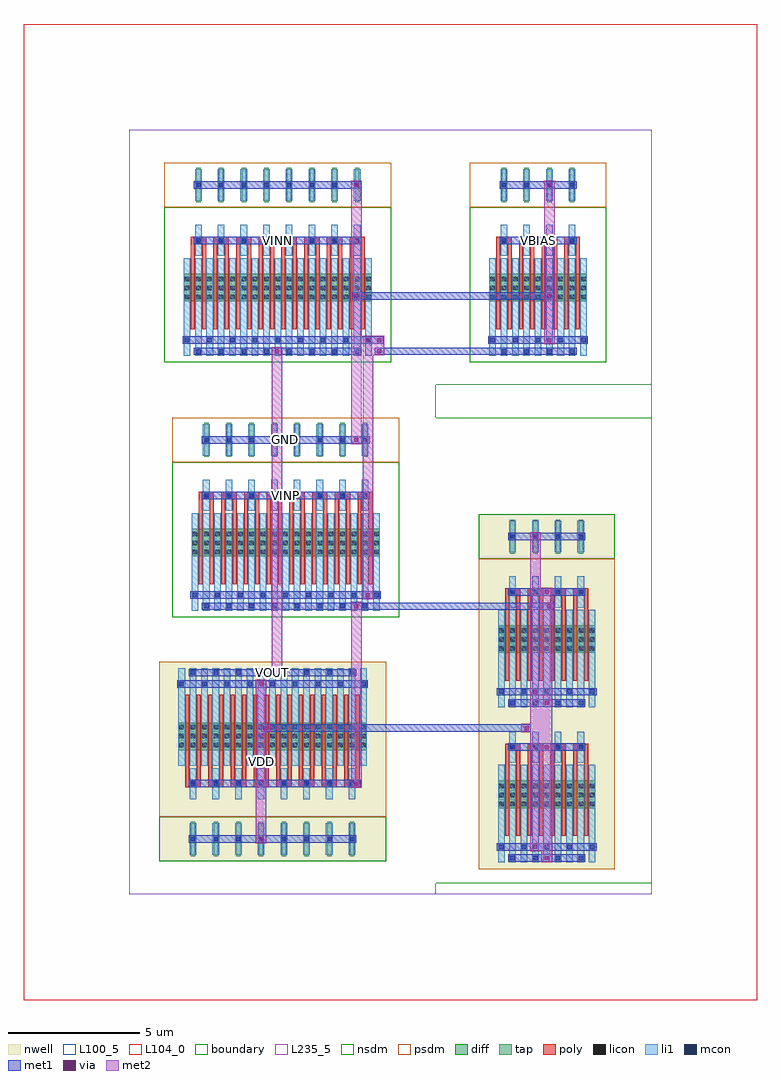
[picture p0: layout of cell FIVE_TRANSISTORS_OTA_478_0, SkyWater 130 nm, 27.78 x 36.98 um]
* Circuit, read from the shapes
.subckt FIVE_TRANSISTORS_OTA_478_0 GND VBIAS VDD VINN VINP VOUT
XM1 VOUT VINN n1 GND sky130_fd_pr__nfet_01v8 w=1.05 l=0.15 m=16
XM2 n2 VINP n1 GND sky130_fd_pr__nfet_01v8 w=1.05 l=0.15 m=16
XM3 n1 VBIAS GND GND sky130_fd_pr__nfet_01v8 w=1.05 l=0.15 m=8
XM4 VOUT n2 VDD VDD sky130_fd_pr__pfet_01v8 w=1.05 l=0.15 m=16
XM5 n2 n2 VDD VDD sky130_fd_pr__pfet_01v8 w=1.05 l=0.15 m=16
.ends

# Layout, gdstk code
from math import pi, radians
import gdstk
lib = gdstk.Library(unit=1e-6, precision=1e-09)
def R(c, l, rs):  # rectangles x0, y0, x1, y1
    for r in rs: c.add(gdstk.rectangle(r[:2], r[2:], *l))
def A(c, l, x, y, w, h, nx, ny, dx, dy):  # array of equal rectangles
    R(c, l, [(x+i*dx, y+j*dy, x+i*dx+w, y+j*dy+h) for i in range(nx) for j in range(ny)])
def P(c, l, *ps):  # polygons
    for p in ps: c.add(gdstk.Polygon(p, *l))
nwell = (64, 20)
diff = (65, 20)
tap = (65, 44)
poly = (66, 20)
licon = (66, 44)
li1 = (67, 20)
mcon = (67, 44)
met1 = (68, 20)
via = (68, 44)
met2 = (69, 20)
nsdm = (93, 44)
psdm = (94, 20)
L100_5 = (100, 5)
L104_0 = (104, 0)
boundary = (235, 4)
L235_5 = (235, 5)

dcl_pmos_s_58408510_x4_y = lib.new_cell('DCL_PMOS_S_58408510_X4_Y2_1746738309')
R(dcl_pmos_s_58408510_x4_y, nwell, [(1.39,0.54,6.55,13.98)])
R(dcl_pmos_s_58408510_x4_y, diff, [(2.125,2.85,5.815,3.9), (2.125,8.73,5.815,9.78)])
A(dcl_pmos_s_58408510_x4_y, tap, 2.595, 12.495, 0.17, 1.29, 4, 1, 0.86, 0)
A(dcl_pmos_s_58408510_x4_y, poly, 2.39, 1.8, 0.15, 3.36, 8, 2, 0.43, 5.88)
A(dcl_pmos_s_58408510_x4_y, poly, 2.39, 5.025, 0.58, 0.27, 4, 2, 0.86, 5.88)
A(dcl_pmos_s_58408510_x4_y, licon, 2.165, 2.93, 0.17, 0.17, 3, 3, 0.43, 0.34)
A(dcl_pmos_s_58408510_x4_y, licon, 3.025, 2.93, 0.17, 0.17, 3, 3, 0.43, 0.34)
A(dcl_pmos_s_58408510_x4_y, licon, 3.885, 2.93, 0.17, 0.17, 3, 3, 0.43, 0.34)
A(dcl_pmos_s_58408510_x4_y, licon, 4.745, 2.93, 0.17, 0.17, 3, 3, 0.43, 0.34)
A(dcl_pmos_s_58408510_x4_y, licon, 2.595, 5.075, 0.17, 0.17, 4, 2, 0.86, 5.88)
A(dcl_pmos_s_58408510_x4_y, licon, 2.165, 8.81, 0.17, 0.17, 3, 3, 0.43, 0.34)
A(dcl_pmos_s_58408510_x4_y, licon, 3.025, 8.81, 0.17, 0.17, 3, 3, 0.43, 0.34)
A(dcl_pmos_s_58408510_x4_y, licon, 3.885, 8.81, 0.17, 0.17, 3, 3, 0.43, 0.34)
A(dcl_pmos_s_58408510_x4_y, licon, 4.745, 8.81, 0.17, 0.17, 3, 3, 0.43, 0.34)
R(dcl_pmos_s_58408510_x4_y, licon, [(2.595,13.055,2.765,13.225), (2.595,13.055,2.765,13.225), (3.455,13.055,3.625,13.225), (3.455,13.055,3.625,13.225), (4.315,13.055,4.485,13.225), (4.315,13.055,4.485,13.225), (5.175,13.055,5.345,13.225), (5.175,13.055,5.345,13.225)])
A(dcl_pmos_s_58408510_x4_y, li1, 2.125, 0.79, 0.25, 3.7, 9, 2, 0.43, 5.88)
A(dcl_pmos_s_58408510_x4_y, li1, 2.555, 4.57, 0.25, 1.18, 4, 2, 0.86, 5.88)
A(dcl_pmos_s_58408510_x4_y, li1, 2.555, 12.55, 0.25, 1.18, 4, 1, 0.86, 0)
A(dcl_pmos_s_58408510_x4_y, mcon, 2.595, 0.875, 0.17, 0.17, 4, 2, 0.86, 4.2)
A(dcl_pmos_s_58408510_x4_y, mcon, 2.165, 1.295, 0.17, 0.17, 5, 2, 0.86, 5.88)
A(dcl_pmos_s_58408510_x4_y, mcon, 2.595, 6.755, 0.17, 0.17, 4, 2, 0.86, 4.2)
A(dcl_pmos_s_58408510_x4_y, mcon, 2.595, 13.055, 0.17, 0.17, 4, 1, 0.86, 0)
R(dcl_pmos_s_58408510_x4_y, met1, [(2.51,0.82,5.43,1.1), (2.08,1.24,5.86,1.52), (2.51,5.02,5.43,5.3), (2.51,6.7,5.43,6.98), (2.08,7.12,5.86,7.4), (2.51,10.9,5.43,11.18), (2.51,13,5.43,13.28)])
A(dcl_pmos_s_58408510_x4_y, via, 4.325, 1.305, 0.15, 0.15, 1, 3, 0, 5.88)
R(dcl_pmos_s_58408510_x4_y, via, [(3.895,0.885,4.045,1.035), (3.895,5.085,4.045,5.235), (3.895,6.765,4.045,6.915), (3.895,10.965,4.045,11.115)])
R(dcl_pmos_s_58408510_x4_y, met2, [(3.77,0.8,4.17,11.2), (4.2,1.22,4.6,13.3)])
R(dcl_pmos_s_58408510_x4_y, nsdm, [(1.39,12.3,6.55,13.98)])
R(dcl_pmos_s_58408510_x4_y, psdm, [(1.39,0.54,6.55,12.3)])
R(dcl_pmos_s_58408510_x4_y, L100_5, [(0,0,8.17,17.64)])
R(dcl_pmos_s_58408510_x4_y, boundary, [(0,0,8.17,17.64)])

nmos_s_69925134_x4_y1_17 = lib.new_cell('NMOS_S_69925134_X4_Y1_1746738312')
R(nmos_s_69925134_x4_y1_17, diff, [(2.025,3.15,5.715,4.2)])
A(nmos_s_69925134_x4_y1_17, tap, 2.495, 6.915, 0.17, 1.29, 4, 1, 0.86, 0)
A(nmos_s_69925134_x4_y1_17, poly, 2.29, 2.1, 0.15, 3.36, 8, 1, 0.43, 0)
A(nmos_s_69925134_x4_y1_17, poly, 2.29, 5.325, 0.58, 0.27, 4, 1, 0.86, 0)
A(nmos_s_69925134_x4_y1_17, licon, 2.065, 3.23, 0.17, 0.17, 3, 3, 0.43, 0.34)
A(nmos_s_69925134_x4_y1_17, licon, 2.925, 3.23, 0.17, 0.17, 3, 3, 0.43, 0.34)
A(nmos_s_69925134_x4_y1_17, licon, 3.785, 3.23, 0.17, 0.17, 3, 3, 0.43, 0.34)
A(nmos_s_69925134_x4_y1_17, licon, 4.645, 3.23, 0.17, 0.17, 3, 3, 0.43, 0.34)
A(nmos_s_69925134_x4_y1_17, licon, 2.495, 5.375, 0.17, 0.17, 4, 2, 0.86, 2.1)
A(nmos_s_69925134_x4_y1_17, li1, 2.025, 1.09, 0.25, 3.7, 9, 1, 0.43, 0)
A(nmos_s_69925134_x4_y1_17, li1, 2.455, 4.87, 0.25, 1.18, 4, 2, 0.86, 2.1)
A(nmos_s_69925134_x4_y1_17, mcon, 2.495, 1.175, 0.17, 0.17, 4, 2, 0.86, 4.2)
A(nmos_s_69925134_x4_y1_17, mcon, 2.065, 1.595, 0.17, 0.17, 5, 1, 0.86, 0)
A(nmos_s_69925134_x4_y1_17, mcon, 2.495, 7.475, 0.17, 0.17, 4, 1, 0.86, 0)
R(nmos_s_69925134_x4_y1_17, met1, [(2.41,1.12,5.33,1.4), (1.98,1.54,5.76,1.82), (2.41,5.32,5.33,5.6), (2.41,7.42,5.33,7.7)])
R(nmos_s_69925134_x4_y1_17, via, [(4.225,1.605,4.375,1.755), (4.225,7.485,4.375,7.635)])
R(nmos_s_69925134_x4_y1_17, met2, [(4.1,1.52,4.5,7.72)])
R(nmos_s_69925134_x4_y1_17, nsdm, [(1.29,0.84,6.45,6.72)])
R(nmos_s_69925134_x4_y1_17, psdm, [(1.29,6.72,6.45,8.4)])
R(nmos_s_69925134_x4_y1_17, L100_5, [(0,0,8.17,9.66)])
R(nmos_s_69925134_x4_y1_17, boundary, [(0,0,8.17,9.66)])

pmos_s_35671219_x8_y1_17 = lib.new_cell('PMOS_S_35671219_X8_Y1_1746738313')
R(pmos_s_35671219_x8_y1_17, nwell, [(1.89,0.84,10.49,8.4)])
R(pmos_s_35671219_x8_y1_17, diff, [(2.625,3.15,9.755,4.2)])
A(pmos_s_35671219_x8_y1_17, tap, 3.095, 6.915, 0.17, 1.29, 8, 1, 0.86, 0)
A(pmos_s_35671219_x8_y1_17, poly, 2.89, 2.1, 0.15, 3.36, 16, 1, 0.43, 0)
A(pmos_s_35671219_x8_y1_17, poly, 2.89, 5.325, 0.58, 0.27, 8, 1, 0.86, 0)
A(pmos_s_35671219_x8_y1_17, licon, 2.665, 3.23, 0.17, 0.17, 3, 3, 0.43, 0.34)
A(pmos_s_35671219_x8_y1_17, licon, 3.525, 3.23, 0.17, 0.17, 3, 3, 0.43, 0.34)
A(pmos_s_35671219_x8_y1_17, licon, 4.385, 3.23, 0.17, 0.17, 3, 3, 0.43, 0.34)
A(pmos_s_35671219_x8_y1_17, licon, 5.245, 3.23, 0.17, 0.17, 3, 3, 0.43, 0.34)
A(pmos_s_35671219_x8_y1_17, licon, 6.105, 3.23, 0.17, 0.17, 3, 3, 0.43, 0.34)
A(pmos_s_35671219_x8_y1_17, licon, 6.965, 3.23, 0.17, 0.17, 3, 3, 0.43, 0.34)
A(pmos_s_35671219_x8_y1_17, licon, 7.825, 3.23, 0.17, 0.17, 3, 3, 0.43, 0.34)
A(pmos_s_35671219_x8_y1_17, licon, 8.685, 3.23, 0.17, 0.17, 3, 3, 0.43, 0.34)
A(pmos_s_35671219_x8_y1_17, licon, 3.095, 5.375, 0.17, 0.17, 8, 2, 0.86, 2.1)
A(pmos_s_35671219_x8_y1_17, li1, 2.625, 1.09, 0.25, 3.7, 17, 1, 0.43, 0)
A(pmos_s_35671219_x8_y1_17, li1, 3.055, 4.87, 0.25, 1.18, 8, 2, 0.86, 2.1)
A(pmos_s_35671219_x8_y1_17, mcon, 3.095, 1.175, 0.17, 0.17, 8, 2, 0.86, 4.2)
A(pmos_s_35671219_x8_y1_17, mcon, 2.665, 1.595, 0.17, 0.17, 9, 1, 0.86, 0)
A(pmos_s_35671219_x8_y1_17, mcon, 3.095, 7.475, 0.17, 0.17, 8, 1, 0.86, 0)
R(pmos_s_35671219_x8_y1_17, met1, [(3.01,1.12,9.37,1.4), (2.58,1.54,9.8,1.82), (3.01,5.32,9.37,5.6), (3.01,7.42,9.37,7.7)])
R(pmos_s_35671219_x8_y1_17, via, [(6.545,1.605,6.695,1.755), (6.545,7.485,6.695,7.635)])
R(pmos_s_35671219_x8_y1_17, met2, [(6.42,1.52,6.82,7.72)])
R(pmos_s_35671219_x8_y1_17, nsdm, [(1.89,6.72,10.49,8.4)])
R(pmos_s_35671219_x8_y1_17, psdm, [(1.89,0.84,10.49,6.72)])
R(pmos_s_35671219_x8_y1_17, L100_5, [(0,0,11.61,9.66)])
R(pmos_s_35671219_x8_y1_17, boundary, [(0,0,11.61,9.66)])

nmos_4t_75119689_x8_y1_1 = lib.new_cell('NMOS_4T_75119689_X8_Y1_1746738311')
R(nmos_4t_75119689_x8_y1_1, diff, [(2.425,3.15,9.555,4.2)])
A(nmos_4t_75119689_x8_y1_1, tap, 2.895, 6.915, 0.17, 1.29, 8, 1, 0.86, 0)
A(nmos_4t_75119689_x8_y1_1, poly, 2.69, 2.1, 0.15, 3.36, 16, 1, 0.43, 0)
A(nmos_4t_75119689_x8_y1_1, poly, 2.69, 5.325, 0.58, 0.27, 8, 1, 0.86, 0)
A(nmos_4t_75119689_x8_y1_1, licon, 2.465, 3.23, 0.17, 0.17, 3, 3, 0.43, 0.34)
A(nmos_4t_75119689_x8_y1_1, licon, 3.325, 3.23, 0.17, 0.17, 3, 3, 0.43, 0.34)
A(nmos_4t_75119689_x8_y1_1, licon, 4.185, 3.23, 0.17, 0.17, 3, 3, 0.43, 0.34)
A(nmos_4t_75119689_x8_y1_1, licon, 5.045, 3.23, 0.17, 0.17, 3, 3, 0.43, 0.34)
A(nmos_4t_75119689_x8_y1_1, licon, 5.905, 3.23, 0.17, 0.17, 3, 3, 0.43, 0.34)
A(nmos_4t_75119689_x8_y1_1, licon, 6.765, 3.23, 0.17, 0.17, 3, 3, 0.43, 0.34)
A(nmos_4t_75119689_x8_y1_1, licon, 7.625, 3.23, 0.17, 0.17, 3, 3, 0.43, 0.34)
A(nmos_4t_75119689_x8_y1_1, licon, 8.485, 3.23, 0.17, 0.17, 3, 3, 0.43, 0.34)
A(nmos_4t_75119689_x8_y1_1, licon, 2.895, 5.375, 0.17, 0.17, 8, 2, 0.86, 2.1)
A(nmos_4t_75119689_x8_y1_1, li1, 2.425, 1.09, 0.25, 3.7, 17, 1, 0.43, 0)
A(nmos_4t_75119689_x8_y1_1, li1, 2.855, 4.87, 0.25, 1.18, 8, 2, 0.86, 2.1)
A(nmos_4t_75119689_x8_y1_1, mcon, 2.895, 1.175, 0.17, 0.17, 8, 2, 0.86, 4.2)
A(nmos_4t_75119689_x8_y1_1, mcon, 2.465, 1.595, 0.17, 0.17, 9, 1, 0.86, 0)
A(nmos_4t_75119689_x8_y1_1, mcon, 2.895, 7.475, 0.17, 0.17, 8, 1, 0.86, 0)
R(nmos_4t_75119689_x8_y1_1, met1, [(2.81,1.12,9.17,1.4), (2.38,1.54,9.6,1.82), (2.81,5.32,9.17,5.6), (2.81,7.42,9.17,7.7)])
R(nmos_4t_75119689_x8_y1_1, nsdm, [(1.69,0.84,10.29,6.72)])
R(nmos_4t_75119689_x8_y1_1, psdm, [(1.69,6.72,10.29,8.4)])
R(nmos_4t_75119689_x8_y1_1, L100_5, [(0,0,11.61,9.66)])
R(nmos_4t_75119689_x8_y1_1, boundary, [(0,0,11.61,9.66)])

nmos_4t_28601550_x8_y1_1 = lib.new_cell('NMOS_4T_28601550_X8_Y1_1746738310')
R(nmos_4t_28601550_x8_y1_1, diff, [(2.125,3.15,9.255,4.2)])
A(nmos_4t_28601550_x8_y1_1, tap, 2.595, 6.915, 0.17, 1.29, 8, 1, 0.86, 0)
A(nmos_4t_28601550_x8_y1_1, poly, 2.39, 2.1, 0.15, 3.36, 16, 1, 0.43, 0)
A(nmos_4t_28601550_x8_y1_1, poly, 2.39, 5.325, 0.58, 0.27, 8, 1, 0.86, 0)
A(nmos_4t_28601550_x8_y1_1, licon, 2.165, 3.23, 0.17, 0.17, 3, 3, 0.43, 0.34)
A(nmos_4t_28601550_x8_y1_1, licon, 3.025, 3.23, 0.17, 0.17, 3, 3, 0.43, 0.34)
A(nmos_4t_28601550_x8_y1_1, licon, 3.885, 3.23, 0.17, 0.17, 3, 3, 0.43, 0.34)
A(nmos_4t_28601550_x8_y1_1, licon, 4.745, 3.23, 0.17, 0.17, 3, 3, 0.43, 0.34)
A(nmos_4t_28601550_x8_y1_1, licon, 5.605, 3.23, 0.17, 0.17, 3, 3, 0.43, 0.34)
A(nmos_4t_28601550_x8_y1_1, licon, 6.465, 3.23, 0.17, 0.17, 3, 3, 0.43, 0.34)
A(nmos_4t_28601550_x8_y1_1, licon, 7.325, 3.23, 0.17, 0.17, 3, 3, 0.43, 0.34)
A(nmos_4t_28601550_x8_y1_1, licon, 8.185, 3.23, 0.17, 0.17, 3, 3, 0.43, 0.34)
A(nmos_4t_28601550_x8_y1_1, licon, 2.595, 5.375, 0.17, 0.17, 8, 2, 0.86, 2.1)
A(nmos_4t_28601550_x8_y1_1, li1, 2.125, 1.09, 0.25, 3.7, 17, 1, 0.43, 0)
A(nmos_4t_28601550_x8_y1_1, li1, 2.555, 4.87, 0.25, 1.18, 8, 2, 0.86, 2.1)
A(nmos_4t_28601550_x8_y1_1, mcon, 2.595, 1.175, 0.17, 0.17, 8, 2, 0.86, 4.2)
A(nmos_4t_28601550_x8_y1_1, mcon, 2.165, 1.595, 0.17, 0.17, 9, 1, 0.86, 0)
A(nmos_4t_28601550_x8_y1_1, mcon, 2.595, 7.475, 0.17, 0.17, 8, 1, 0.86, 0)
R(nmos_4t_28601550_x8_y1_1, met1, [(2.51,1.12,8.87,1.4), (2.08,1.54,9.3,1.82), (2.51,5.32,8.87,5.6), (2.51,7.42,8.87,7.7)])
R(nmos_4t_28601550_x8_y1_1, nsdm, [(1.39,0.84,9.99,6.72)])
R(nmos_4t_28601550_x8_y1_1, psdm, [(1.39,6.72,9.99,8.4)])
R(nmos_4t_28601550_x8_y1_1, L100_5, [(0,0,11.61,9.66)])
R(nmos_4t_28601550_x8_y1_1, boundary, [(0,0,11.61,9.66)])

five_transistors_ota_478 = lib.new_cell('FIVE_TRANSISTORS_OTA_478_0')
R(five_transistors_ota_478, met1, [(8.44,4.06,8.76,4.34), (8.44,4.06,8.76,4.34), (8.44,4.06,8.76,4.34), (8.44,4.06,8.76,4.34), (5,6.16,5.32,6.44), (5,6.16,5.32,6.44), (5.16,6.16,15.05,6.44), (14.89,6.16,15.21,6.44), (14.89,6.16,15.21,6.44), (5.43,8.26,5.75,8.54), (5.43,8.26,5.75,8.54), (8.44,10.78,8.76,11.06), (8.44,10.78,8.76,11.06), (8.44,10.78,8.76,11.06), (8.44,10.78,8.76,11.06), (9.03,10.78,15.91,11.06), (15.75,10.78,16.07,11.06), (15.75,10.78,16.07,11.06), (8.87,11.2,9.19,11.48), (8.87,11.2,9.19,11.48), (8.87,11.2,9.19,11.48), (8.87,11.2,9.19,11.48), (8.44,17.08,8.76,17.36), (8.44,17.08,8.76,17.36), (8.44,17.08,8.76,17.36), (8.44,17.08,8.76,17.36), (5.43,20.44,5.75,20.72), (5.43,20.44,5.75,20.72), (9.3,20.44,9.62,20.72), (9.3,20.44,9.62,20.72), (9.46,20.44,14.19,20.72), (8.87,20.86,9.19,21.14), (8.87,20.86,9.19,21.14), (8.87,20.86,9.19,21.14), (8.87,20.86,9.19,21.14), (9.03,20.86,9.46,21.14), (9.3,20.86,9.62,21.14), (9.3,20.86,9.62,21.14), (8.44,22.54,8.76,22.82), (8.44,22.54,8.76,22.82), (8.6,22.54,15.91,22.82), (15.75,22.54,16.07,22.82), (15.75,22.54,16.07,22.82), (8.44,26.74,8.76,27.02), (8.44,26.74,8.76,27.02), (8.44,26.74,8.76,27.02), (8.44,26.74,8.76,27.02)])
P(five_transistors_ota_478, met1, [(0,0),(0,0),(0,0),(0,0)],
  [(0,0),(0,0),(0,0),(0,0)],
  [(0,0),(0,0),(0,0),(0,0)],
  [(0,0),(0,0),(0,0),(0,0)],
  [(0,0),(0,0),(0,0),(0,0)],
  [(0,0),(0,0),(0,0),(0,0)],
  [(0,0),(0,0),(0,0),(0,0)],
  [(0,0),(0,0),(0,0),(0,0)],
  [(0,0),(0,0),(0,0),(0,0)],
  [(0,0),(0,0),(0,0),(0,0)],
  [(0,0),(0,0),(0,0),(0,0)],
  [(0,0),(0,0),(0,0),(0,0)],
  [(0,0),(0,0),(0,0),(0,0)],
  [(0,0),(0,0),(0,0),(0,0)],
  [(0,0),(0,0),(0,0),(0,0)],
  [(0,0),(0,0),(0,0),(0,0)],
  [(0,0),(0,0),(0,0),(0,0)])
R(five_transistors_ota_478, via, [(8.525,4.125,8.675,4.275), (8.525,4.125,8.675,4.275), (8.525,4.125,8.675,4.275), (8.525,4.125,8.675,4.275), (5.085,6.225,5.235,6.375), (5.085,6.225,5.235,6.375), (14.975,6.225,15.125,6.375), (14.975,6.225,15.125,6.375), (5.515,8.325,5.665,8.475), (5.515,8.325,5.665,8.475), (8.525,10.845,8.675,10.995), (8.525,10.845,8.675,10.995), (8.525,10.845,8.675,10.995), (8.525,10.845,8.675,10.995), (15.835,10.845,15.985,10.995), (15.835,10.845,15.985,10.995), (8.955,11.265,9.105,11.415), (8.955,11.265,9.105,11.415), (8.955,11.265,9.105,11.415), (8.955,11.265,9.105,11.415), (8.525,17.145,8.675,17.295), (8.525,17.145,8.675,17.295), (8.525,17.145,8.675,17.295), (8.525,17.145,8.675,17.295), (5.515,20.505,5.665,20.655), (5.515,20.505,5.665,20.655), (9.385,20.505,9.535,20.655), (9.385,20.505,9.535,20.655), (8.955,20.925,9.105,21.075), (8.955,20.925,9.105,21.075), (8.955,20.925,9.105,21.075), (8.955,20.925,9.105,21.075), (9.385,20.925,9.535,21.075), (9.385,20.925,9.535,21.075), (8.525,22.605,8.675,22.755), (8.525,22.605,8.675,22.755), (15.835,22.605,15.985,22.755), (15.835,22.605,15.985,22.755), (8.525,26.805,8.675,26.955), (8.525,26.805,8.675,26.955), (8.525,26.805,8.675,26.955), (8.525,26.805,8.675,26.955)])
R(five_transistors_ota_478, met2, [(8.4,4.04,8.8,4.36), (8.4,4.04,8.8,4.36), (8.4,4.04,8.8,4.36), (8.4,4.04,8.8,4.36), (8.4,4.2,8.8,10.92), (4.96,6.14,5.36,6.46), (4.96,6.14,5.36,6.46), (14.85,6.14,15.25,6.46), (14.85,6.14,15.25,6.46), (5.39,8.24,5.79,8.56), (5.39,8.24,5.79,8.56), (5.39,8.4,5.79,20.58), (8.4,10.76,8.8,11.08), (8.4,10.76,8.8,11.08), (8.4,10.76,8.8,11.08), (8.4,10.76,8.8,11.08), (15.71,10.76,16.11,11.08), (15.71,10.76,16.11,11.08), (8.83,11.18,9.23,11.5), (8.83,11.18,9.23,11.5), (8.83,11.18,9.23,11.5), (8.83,11.18,9.23,11.5), (8.83,11.34,9.23,21), (8.4,17.06,8.8,17.38), (8.4,17.06,8.8,17.38), (8.4,17.06,8.8,17.38), (8.4,17.06,8.8,17.38), (8.4,17.22,8.8,26.88), (5.39,20.42,5.79,20.74), (5.39,20.42,5.79,20.74), (9.26,20.42,9.66,20.74), (9.26,20.42,9.66,20.74), (9.26,20.58,9.66,21), (8.83,20.84,9.23,21.16), (8.83,20.84,9.23,21.16), (8.83,20.84,9.23,21.16), (8.83,20.84,9.23,21.16), (9.26,20.84,9.66,21.16), (9.26,20.84,9.66,21.16), (8.4,22.52,8.8,22.84), (8.4,22.52,8.8,22.84), (15.71,22.52,16.11,22.84), (15.71,22.52,16.11,22.84), (8.4,26.72,8.8,27.04), (8.4,26.72,8.8,27.04), (8.4,26.72,8.8,27.04), (8.4,26.72,8.8,27.04)])
P(five_transistors_ota_478, met2, [(0,0),(0,0),(0,0),(0,0)],
  [(0,0),(0,0),(0,0),(0,0)],
  [(0,0),(0,0),(0,0),(0,0)],
  [(0,0),(0,0),(0,0),(0,0)],
  [(0,0),(0,0),(0,0),(0,0)])
R(five_transistors_ota_478, L104_0, [(-4,-4,23.78,32.98)])
R(five_transistors_ota_478, L235_5, [(0,0,19.78,28.98)])
five_transistors_ota_478.add(gdstk.Reference(dcl_pmos_s_58408510_x4_y, (19.78,0.42), rotation=pi, x_reflection=True))
five_transistors_ota_478.add(gdstk.Reference(nmos_s_69925134_x4_y1_17, (11.61,19.32)))
five_transistors_ota_478.add(gdstk.Reference(pmos_s_35671219_x8_y1_17, (11.61,9.66), rotation=pi))
five_transistors_ota_478.add(gdstk.Reference(nmos_4t_75119689_x8_y1_1, (11.61,19.32), rotation=pi, x_reflection=True))
five_transistors_ota_478.add(gdstk.Reference(nmos_4t_28601550_x8_y1_1, (11.61,9.66), rotation=pi, x_reflection=True))
five_transistors_ota_478.add(gdstk.Label('VDD', (4.99,5.04), layer=69, texttype=5))
five_transistors_ota_478.add(gdstk.Label('VBIAS', (15.48,24.78), layer=68, texttype=5))
five_transistors_ota_478.add(gdstk.Label('GND', (5.92,17.22), layer=68, texttype=5))
five_transistors_ota_478.add(gdstk.Label('VOUT', (5.42,8.4), layer=68, texttype=5))
five_transistors_ota_478.add(gdstk.Label('VINN', (5.62,24.78), layer=68, texttype=5))
five_transistors_ota_478.add(gdstk.Label('VINP', (5.92,15.12), layer=68, texttype=5))

lib.write_gds('FIVE_TRANSISTORS_OTA_478_0.gds')
